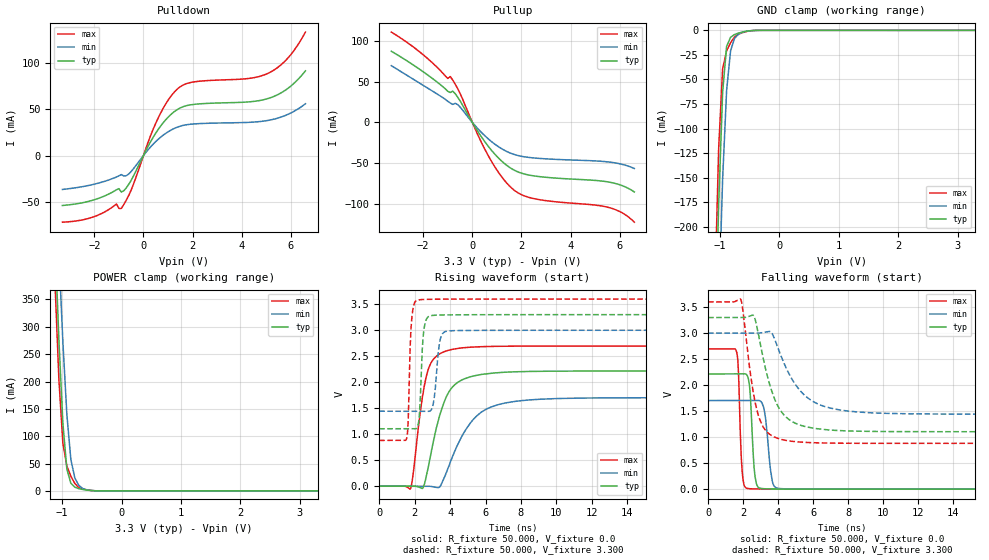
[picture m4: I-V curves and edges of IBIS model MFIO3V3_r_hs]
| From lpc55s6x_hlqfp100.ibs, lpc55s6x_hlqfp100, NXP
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|   Model MFIO3V3_r_hs
[Model] MFIO3V3_r_hs
Model_type I/O
Polarity   Non-Inverting
Enable   Active-Low
Vinl =  0.990V
Vinh =  2.310V
Vmeas =  1.650V
Cref =  0.0F
Rref =  100.000
Vref =  0.0V
C_comp   1.925pF   1.906pF   1.947pF
C_comp_pullup   1.145pF   1.141pF   1.152pF
C_comp_pulldown   0.641pF   0.633pF   0.647pF
[Model Spec]
Vinh   2.310V   2.100V   2.520V
Vinl   0.990V   0.900V   1.080V
Vmeas   1.650V   1.500V   1.800V
Vref   0.0V   0.0V   0.0V
Cref   0.0F   0.0F   0.0F
Rref   100.000   100.000   100.000
[Temperature Range]   25.000   0.125k   -40.000
[Voltage Range]   3.300V   3.000V   3.600V
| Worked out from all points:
|   slope of the pulldown table from 0 to 0.495 V, typ, clamps not added: 20.7 ohm
|   slope of the pullup table from 0 to 0.495 V, typ, clamps not added: 21.4 ohm
|   GND clamp passes 1 mA (typ) near -0.56 V on its own axis
|   POWER clamp passes 1 mA (typ) near -0.54 V on its own axis
|   rising waveform, R_fixture 50.000, V_fixture 0.0: 20-80 % time 1.05ns typ, 1.66ns min, 671ps max; typ from 0 V to 2.21 V
|   rising waveform, R_fixture 50.000, V_fixture 3.300: 20-80 % time 177ps typ, 249ps min, 147ps max; typ from 1.1 V to 3.3 V
|   falling waveform, R_fixture 50.000, V_fixture 0.0: 20-80 % time 203ps typ, 295ps min, 162ps max; typ from 2.21 V to 0 V
|   falling waveform, R_fixture 50.000, V_fixture 3.300: 20-80 % time 1.14ns typ, 1.67ns min, 742ps max; typ from 3.3 V to 1.1 V
[Pulldown]
|Voltage   I(typ)   I(min)   I(max)
-3.3V     -53.7mA    -36.43mA   -71.67mA
-2.1V     -48.29mA   -31.37mA   -66.51mA
-1.1V     -36.82mA   -23.05mA   -52.1mA
-900mV    -39.2mA    -20.39mA   -56.91mA
-600mV    -30.96mA   -19.83mA   -42.97mA
600mV     28.07mA    17.5mA     40.4mA
1V        41.17mA    25.53mA    59.41mA
1.4V      49.87mA    30.79mA    72.04mA
2V        54.93mA    33.94mA    79.03mA
5V        60.84mA    37.53mA    87.68mA
5.9V      72.62mA    44.52mA    105.4mA
6.6V      91.19mA    55.78mA    132.9mA
[Pullup]
|Voltage   I(typ)   I(min)   I(max)
-3.3V     87.16mA    69.54mA    110.7mA
-2.1V     64.12mA    47.22mA    85.31mA
-1V       38.1mA     25.85mA    53.88mA
-900mV    36.64mA    23.75mA    56.16mA
-800mV    38.25mA    22.02mA    51.93mA
-600mV    31.06mA    21.93mA    41.58mA
700mV     -31.25mA   -21.55mA   -43.56mA
1.2V      -47.6mA    -32.42mA   -66.97mA
1.7V      -58.52mA   -39.3mA    -83.05mA
2.6V      -66.01mA   -43.88mA   -94.06mA
5.6V      -73.4mA    -48.74mA   -104.7mA
6.6V      -85.32mA   -56.6mA    -122.4mA
[GND_clamp]
|Voltage   I(typ)   I(min)   I(max)
-3.3V     -7.222A    -7.177A    -7.278A
-1.089V   -337.1mA   -440.8mA   -274.1mA
-1.022V   -178.2mA   -284.2mA   -121mA
-955mV    -63.05mA   -151.6mA   -39.25mA
-888mV    -16.33mA   -61.34mA   -20.9mA
-821mV    -7.066mA   -20.84mA   -12.66mA
-754mV    -4.265mA   -8.157mA   -6.693mA
-687mV    -2.794mA   -3.896mA   -3.841mA
-620mV    -1.725mA   -1.894mA   -2.339mA
-419mV    -112.4uA   -138.2uA   -135uA
3.3V      0A         0A         -7.009uA
[POWER_clamp]
|Voltage   I(typ)   I(min)   I(max)
-3.3V     8.016A     7.986A     8.074A
-1.122V   463.7mA    614.3mA    385mA
-1.055V   276.3mA    434.9mA    203.9mA
-988mV    124mA      272.3mA    87.13mA
-921mV    39.96mA    140.1mA    45.6mA
-854mV    14.17mA    57.77mA    27.03mA
-787mV    6.855mA    23.75mA    13.68mA
-720mV    4.075mA    10.22mA    6.123mA
-653mV    2.616mA    4.368mA    3.615mA
-586mV    1.55mA     1.867mA    2.107mA
-452mV    281.1uA    359.9uA    338.7uA
3.3V      0A         0A         7.017uA
[Ramp]
| variable   typ   min   max
dV/dt_r   1.329/1.050n   1.022/1.662n   1.618/0.671n
dV/dt_f   1.317/1.135n   0.935/1.672n   1.632/0.745n
R_load = 50.000
[Rising Waveform]
R_fixture= 50.000
V_fixture= 0.0
V_fixture_min= 0.0
V_fixture_max= 0.0
|time   V(typ)   V(min)   V(max)
0s        11.38nV    124.8nV    46.5nV
1.76ns    11.35uV    -454.5nV   -52.4mV
1.89ns    125.5uV    -342.1nV   156mV
2.47ns    -34.61mV   71.44uV    1.767V
2.93ns    645.9mV    -5.154mV   2.378V
3.68ns    1.636V     173.9mV    2.589V
4.98ns    2.088V     1.138V     2.67V
6.67ns    2.183V     1.564V     2.691V
11.05ns   2.214V     1.693V     2.696V
100ns     2.215V     1.704V     2.696V
[Rising Waveform]
R_fixture= 50.000
V_fixture= 3.300
V_fixture_min= 3.000
V_fixture_max= 3.600
|time   V(typ)   V(min)   V(max)
0s        1.105V     1.442V     880.4mV
1.55ns    1.105V     1.442V     919.2mV
1.84ns    1.105V     1.442V     3.234V
2.22ns    1.223V     1.442V     3.583V
2.38ns    2.203V     1.442V     3.59V
2.7ns     3.235V     1.441V     3.594V
3.07ns    3.287V     1.618V     3.596V
3.47ns    3.293V     2.857V     3.598V
4.1ns     3.296V     2.991V     3.599V
100ns     3.3V       3V         3.6V
[Falling Waveform]
R_fixture= 50.000
V_fixture= 0.0
V_fixture_min= 0.0
V_fixture_max= 0.0
|time   V(typ)   V(min)   V(max)
0s        2.215V     1.704V     2.696V
1.63ns    2.215V     1.704V     2.641V
1.73ns    2.215V     1.704V     2.3V
1.97ns    2.216V     1.704V     265.9mV
2.38ns    1.949V     1.704V     8.551mV
2.68ns    252.6mV    1.704V     4.207mV
3.21ns    8.403mV    1.523V     1.553mV
3.68ns    3.793mV    139.7mV    954.6uV
4.26ns    2.189mV    8.488mV    558.3uV
100ns     15.88nV    132.9nV    49.27nV
[Falling Waveform]
R_fixture= 50.000
V_fixture= 3.300
V_fixture_min= 3.000
V_fixture_max= 3.600
|time   V(typ)   V(min)   V(max)
0s        3.3V       3V         3.6V
1.87ns    3.3V       3V         3.648V
2.61ns    3.334V     3V         1.81V
3.09ns    2.622V     3.009V     1.234V
3.56ns    1.971V     3.029V     1.046V
3.83ns    1.711V     2.868V     996.5mV
5.1ns     1.252V     1.964V     910mV
6.88ns    1.14V      1.569V     886.3mV
10.87ns   1.107V     1.453V     880.6mV
100ns     1.105V     1.442V     880.4mV
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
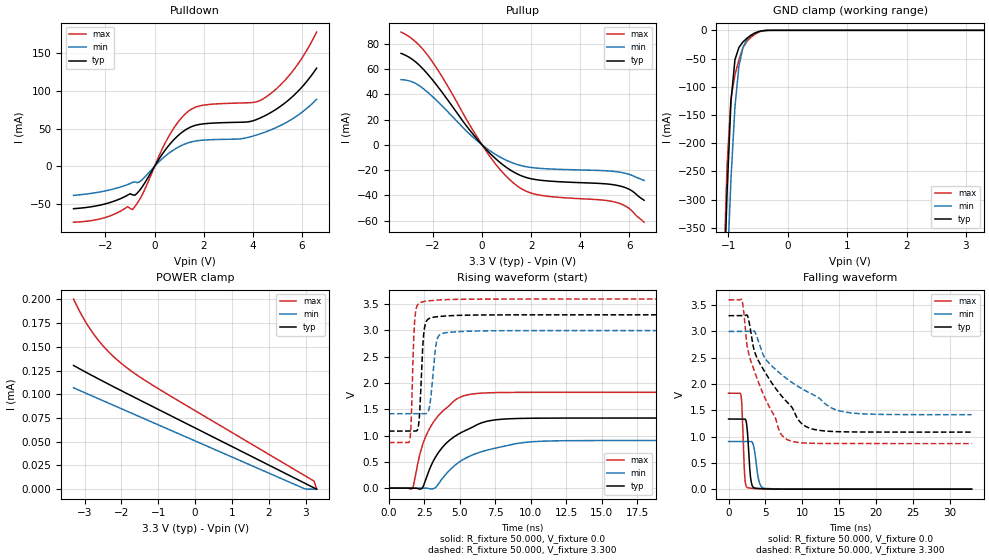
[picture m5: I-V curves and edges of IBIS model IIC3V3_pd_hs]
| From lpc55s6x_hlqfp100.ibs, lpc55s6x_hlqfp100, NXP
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|   Model IIC3V3_pd_hs
[Model] IIC3V3_pd_hs
Model_type I/O
Polarity   Non-Inverting
Enable   Active-Low
Vinl =  0.990V
Vinh =  2.310V
Vmeas =  1.650V
Cref =  0.0F
Rref =  100.000
Vref =  0.0V
C_comp   2.434pF   2.433pF   2.440pF
C_comp_pullup   0.538pF   0.435pF   0.627pF
C_comp_pulldown   1.615pF   1.554pF   1.667pF
[Model Spec]
Vinh   2.310V   2.100V   2.520V
Vinl   0.990V   0.900V   1.080V
Vmeas   1.650V   1.500V   1.800V
Vref   0.0V   0.0V   0.0V
Cref   0.0F   0.0F   0.0F
Rref   100.000   100.000   100.000
[Temperature Range]   25.000   0.125k   -40.000
[Voltage Range]   3.300V   3.000V   3.600V
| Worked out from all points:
|   slope of the pulldown table from 0 to 0.495 V, typ, clamps not added: 20.4 ohm
|   slope of the pullup table from 0 to 0.495 V, typ, clamps not added: 49.8 ohm
|   GND clamp passes 1 mA (typ) near -0.43 V on its own axis
|   rising waveform, R_fixture 50.000, V_fixture 0.0: 20-80 % time 2.43ns typ, 3.18ns min, 1.81ns max; typ from 0 V to 1.33 V
|   rising waveform, R_fixture 50.000, V_fixture 3.300: 20-80 % time 241ps typ, 336ps min, 194ps max; typ from 1.08 V to 3.3 V
|   falling waveform, R_fixture 50.000, V_fixture 0.0: 20-80 % time 379ps typ, 544ps min, 287ps max; typ from 1.33 V to 0 V
|   falling waveform, R_fixture 50.000, V_fixture 3.300: 20-80 % time 5.55ns typ, 7.91ns min, 3.87ns max; typ from 3.3 V to 1.08 V
[Pulldown]
|Voltage   I(typ)   I(min)   I(max)
-3.3V     -56mA      -38.4mA    -73.87mA
-2.1V     -50.37mA   -33.07mA   -68.52mA
-1.1V     -38.15mA   -24.11mA   -53.37mA
-900mV    -37.61mA   -21.16mA   -57.18mA
-500mV    -26.92mA   -17.4mA    -37.43mA
500mV     24.51mA    15.34mA    35.14mA
1.2V      47.07mA    29.16mA    67.89mA
1.9V      55.94mA    34.55mA    80.54mA
3.8V      58.93mA    38.31mA    84.23mA
4.5V      67.15mA    45.39mA    91.04mA
5.6V      91.85mA    62.59mA    125mA
6.6V      130mA      88.72mA    177.8mA
[Pullup]
|Voltage   I(typ)   I(min)   I(max)
-3.3V     72.4mA     51.62mA    89.28mA
-2.8V     67.12mA    49.5mA     83.13mA
-2.2V     55.65mA    41.38mA    70.52mA
-1.6V     40.88mA    30.27mA    53.04mA
-600mV    14.09mA    10.23mA    18.91mA
200mV     -4.263mA   -2.967mA   -5.9mA
800mV     -15.05mA   -10.35mA   -21.01mA
1.4V      -22.69mA   -15.36mA   -32.04mA
2.4V      -28.05mA   -18.66mA   -39.95mA
5.5V      -32.06mA   -21.31mA   -45.72mA
6V        -35.26mA   -23.41mA   -50.46mA
6.6V      -43.87mA   -28.15mA   -61.22mA
[GND_clamp]
|Voltage   I(typ)   I(min)   I(max)
-3.3V     -10.05A    -9.18A     -11.33A
-1.089V   -516.5mA   -633.7mA   -475mA
-1.022V   -291.9mA   -436.3mA   -243.2mA
-955mV    -126mA     -264mA     -120.7mA
-888mV    -52.17mA   -135.6mA   -79.12mA
-821mV    -30.44mA   -63.69mA   -52.12mA
-754mV    -20.67mA   -30.69mA   -31.05mA
-687mV    -14.19mA   -15.97mA   -19.65mA
-553mV    -5.021mA   -4.512mA   -7.044mA
-419mV    -659.6uA   -714.3uA   -896.4uA
-285mV    -20.38uA   -37.42uA   -22.84uA
3.3V      0A         0A         0A
[POWER_clamp]
|Voltage   I(typ)   I(min)   I(max)
-3.3V     130.3uA    106.8uA    200.3uA
-3.132V   126.7uA    103.9uA    187.1uA
-2.998V   123.9uA    101.7uA    177.8uA
-2.73V    118.4uA    97.1uA     162.1uA
-2.529V   114.3uA    93.69uA    152.3uA
-2.328V   110.2uA    90.28uA    143.9uA
-1.926V   102.2uA    83.47uA    130.1uA
-1.524V   94.32uA    76.66uA    118.8uA
-921mV    82.52uA    66.44uA    104uA
2.965V    6.549uA    592.5nA    14.59uA
3.233V    1.309uA    0A         8.433uA
3.3V      0A         0A         0A
[Ramp]
| variable   typ   min   max
dV/dt_r   0.800/2.433n   0.544/3.184n   1.094/1.812n
dV/dt_f   1.328/5.547n   0.950/7.909n   1.639/3.869n
R_load = 50.000
[Rising Waveform]
R_fixture= 50.000
V_fixture= 0.0
V_fixture_min= 0.0
V_fixture_max= 0.0
|time   V(typ)   V(min)   V(max)
0s        10.23nV    71.93nV    30.73nV
1.632ns   18.86uV    71.42nV    -10.83mV
2.343ns   370.2uV    76.31uV    798.8mV
2.982ns   433.5mV    -16.05mV   1.188V
3.344ns   617mV      25.85mV    1.333V
4.042ns   853.9mV    273.8mV    1.521V
5.586ns   1.119V     594.1mV    1.777V
7.276ns   1.29V      747mV      1.816V
10.76ns   1.331V     891.7mV    1.823V
33ns      1.333V     906mV      1.823V
[Rising Waveform]
R_fixture= 50.000
V_fixture= 3.300
V_fixture_min= 3.000
V_fixture_max= 3.600
|time   V(typ)   V(min)   V(max)
0s        1.085V     1.415V     866.6mV
1.466ns   1.085V     1.415V     907.3mV
1.828ns   1.084V     1.415V     3.224V
2.114ns   1.254V     1.415V     3.516V
2.319ns   2.35V      1.415V     3.542V
2.621ns   3.166V     1.416V     3.558V
2.907ns   3.237V     1.621V     3.567V
3.355ns   3.261V     2.784V     3.579V
3.89ns    3.275V     2.952V     3.587V
33ns      3.298V     2.999V     3.598V
[Falling Waveform]
R_fixture= 50.000
V_fixture= 0.0
V_fixture_min= 0.0
V_fixture_max= 0.0
|time   V(typ)   V(min)   V(max)
0s        1.333V     906.1mV    1.824V
1.671ns   1.333V     906.1mV    1.8V
1.839ns   1.333V     906.1mV    1.516V
2.194ns   1.335V     906.1mV    248.2mV
2.592ns   1.034V     906.1mV    28.56mV
3.005ns   201.2mV    907.4mV    17.6mV
3.548ns   22.18mV    715.7mV    12.27mV
4.118ns   13.25mV    159.7mV    5.625mV
4.898ns   6.293mV    16.27mV    2.275mV
33ns      662nV      1.301uV    429.9nV
[Falling Waveform]
R_fixture= 50.000
V_fixture= 3.300
V_fixture_min= 3.000
V_fixture_max= 3.600
|time   V(typ)   V(min)   V(max)
0s        3.298V     2.999V     3.598V
1.815ns   3.298V     2.999V     3.606V
2.477ns   3.311V     2.999V     2.767V
2.917ns   3.081V     2.998V     2.483V
3.918ns   2.48V      2.868V     2.086V
5.055ns   2.199V     2.47V      1.699V
7.793ns   1.678V     2.112V     955.7mV
12.03ns   1.124V     1.756V     869.9mV
16.66ns   1.088V     1.45V      866.9mV
33ns      1.085V     1.416V     866.6mV
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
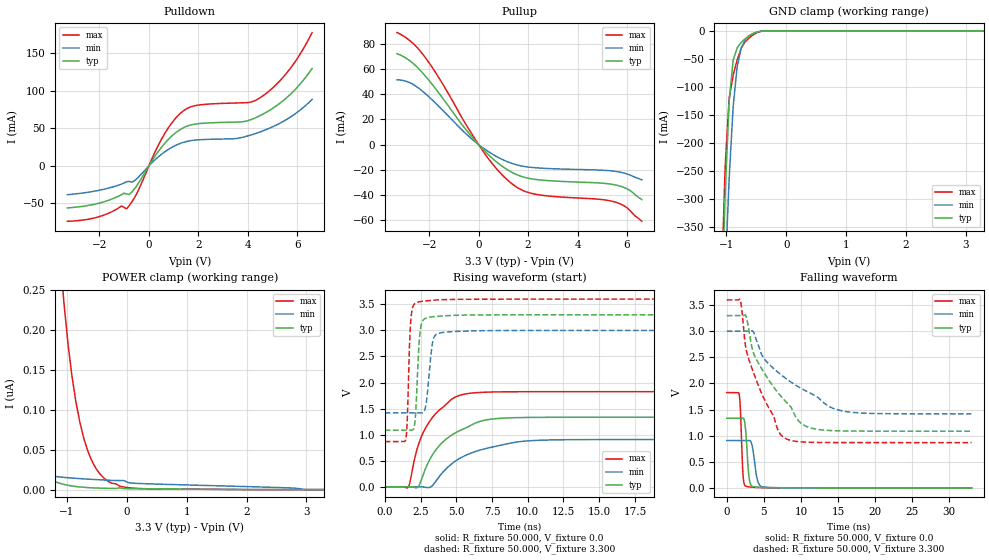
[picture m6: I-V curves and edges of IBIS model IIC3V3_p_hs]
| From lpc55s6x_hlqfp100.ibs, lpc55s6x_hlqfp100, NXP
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|   Model IIC3V3_p_hs
[Model] IIC3V3_p_hs
Model_type I/O
Polarity   Non-Inverting
Enable   Active-Low
Vinl =  0.990V
Vinh =  2.310V
Vmeas =  1.650V
Cref =  0.0F
Rref =  100.000
Vref =  0.0V
C_comp   2.434pF   2.433pF   2.440pF
C_comp_pullup   0.538pF   0.436pF   0.627pF
C_comp_pulldown   1.614pF   1.554pF   1.665pF
[Model Spec]
Vinh   2.310V   2.100V   2.520V
Vinl   0.990V   0.900V   1.080V
Vmeas   1.650V   1.500V   1.800V
Vref   0.0V   0.0V   0.0V
Cref   0.0F   0.0F   0.0F
Rref   100.000   100.000   100.000
[Temperature Range]   25.000   0.125k   -40.000
[Voltage Range]   3.300V   3.000V   3.600V
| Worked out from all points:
|   slope of the pulldown table from 0 to 0.495 V, typ, clamps not added: 20.4 ohm
|   slope of the pullup table from 0 to 0.495 V, typ, clamps not added: 49.8 ohm
|   GND clamp passes 1 mA (typ) near -0.43 V on its own axis
|   rising waveform, R_fixture 50.000, V_fixture 0.0: 20-80 % time 2.44ns typ, 3.19ns min, 1.82ns max; typ from 0 V to 1.33 V
|   rising waveform, R_fixture 50.000, V_fixture 3.300: 20-80 % time 241ps typ, 336ps min, 194ps max; typ from 1.08 V to 3.3 V
|   falling waveform, R_fixture 50.000, V_fixture 0.0: 20-80 % time 379ps typ, 544ps min, 287ps max; typ from 1.33 V to 0 V
|   falling waveform, R_fixture 50.000, V_fixture 3.300: 20-80 % time 5.55ns typ, 7.92ns min, 3.87ns max; typ from 3.3 V to 1.08 V
[Pulldown]
|Voltage   I(typ)   I(min)   I(max)
-3.3V     -56mA      -38.4mA    -73.87mA
-2.1V     -50.37mA   -33.07mA   -68.52mA
-1.1V     -38.15mA   -24.11mA   -53.37mA
-900mV    -37.61mA   -21.16mA   -57.18mA
-500mV    -26.92mA   -17.4mA    -37.43mA
500mV     24.51mA    15.34mA    35.14mA
1.2V      47.07mA    29.16mA    67.89mA
1.9V      55.94mA    34.55mA    80.54mA
3.8V      58.93mA    38.31mA    84.23mA
4.5V      67.16mA    45.4mA     91.05mA
5.6V      91.88mA    62.62mA    125.1mA
6.6V      130mA      88.76mA    177.9mA
[Pullup]
|Voltage   I(typ)   I(min)   I(max)
-3.3V     72.44mA    51.65mA    89.33mA
-2.8V     67.15mA    49.53mA    83.18mA
-2.2V     55.68mA    41.4mA     70.55mA
-1.6V     40.9mA     30.28mA    53.06mA
-600mV    14.09mA    10.23mA    18.92mA
200mV     -4.263mA   -2.967mA   -5.9mA
800mV     -15.05mA   -10.35mA   -21.01mA
1.4V      -22.69mA   -15.36mA   -32.04mA
2.4V      -28.05mA   -18.66mA   -39.95mA
5.5V      -32.06mA   -21.31mA   -45.72mA
6V        -35.26mA   -23.41mA   -50.46mA
6.6V      -43.87mA   -28.15mA   -61.22mA
[GND_clamp]
|Voltage   I(typ)   I(min)   I(max)
-3.3V     -10.05A    -9.18A     -11.33A
-1.089V   -516.5mA   -633.7mA   -475mA
-1.022V   -291.8mA   -436.3mA   -243.2mA
-955mV    -126mA     -264mA     -120.7mA
-888mV    -52.17mA   -135.6mA   -79.11mA
-821mV    -30.43mA   -63.68mA   -52.11mA
-754mV    -20.66mA   -30.68mA   -31.04mA
-687mV    -14.18mA   -15.96mA   -19.64mA
-553mV    -5.013mA   -4.505mA   -7.034mA
-419mV    -652.2uA   -708.2uA   -887.6uA
-285mV    -14.83uA   -32.68uA   -16.3uA
3.3V      0A         0A         0A
[POWER_clamp]
|Voltage   I(typ)   I(min)   I(max)
-3.3V     1.337uA    96.84nA    41.74uA
-2.395V   241.1nA    38.51nA    8.841uA
-2.194V   152.2nA    32.17nA    5.805uA
-1.926V   78.16nA    25.86nA    3.134uA
-1.658V   37.82nA    21.36nA    1.572uA
-1.256V   11.75nA    16.9nA     472.7nA
-1.055V   6.592nA    15.36nA    237.1nA
-921mV    4.605nA    14.51nA    144.1nA
-787mV    3.339nA    13.77nA    84.89nA
-586mV    2.257nA    12.84nA    36.19nA
-318mV    1.588nA    11.83nA    10.67nA
3.3V      0A         0A         0A
[Ramp]
| variable   typ   min   max
dV/dt_r   0.801/2.438n   0.544/3.191n   1.095/1.816n
dV/dt_f   1.329/5.554n   0.950/7.920n   1.640/3.875n
R_load = 50.000
[Rising Waveform]
R_fixture= 50.000
V_fixture= 0.0
V_fixture_min= 0.0
V_fixture_max= 0.0
|time   V(typ)   V(min)   V(max)
0s        11.16nV    74.81nV    32.72nV
1.636ns   21.13uV    74.28nV    -9.633mV
2.345ns   1.006mV    77.15uV    800.3mV
2.981ns   432.7mV    -16.03mV   1.188V
3.312ns   602.9mV    17.15mV    1.322V
4.008ns   844.8mV    263.4mV    1.514V
5.569ns   1.117V     591.9mV    1.777V
7.277ns   1.291V     747.1mV    1.817V
10.77ns   1.332V     892.2mV    1.824V
33ns      1.334V     906.7mV    1.825V
[Rising Waveform]
R_fixture= 50.000
V_fixture= 3.300
V_fixture_min= 3.000
V_fixture_max= 3.600
|time   V(typ)   V(min)   V(max)
0s        1.085V     1.416V     866.9mV
1.461ns   1.085V     1.416V     902.1mV
1.562ns   1.085V     1.416V     1.207V
1.829ns   1.085V     1.416V     3.227V
2.113ns   1.252V     1.416V     3.516V
2.321ns   2.359V     1.416V     3.543V
2.62ns    3.166V     1.417V     3.559V
3.356ns   3.262V     2.787V     3.58V
3.889ns   3.275V     2.953V     3.588V
33ns      3.3V       3V         3.6V
[Falling Waveform]
R_fixture= 50.000
V_fixture= 0.0
V_fixture_min= 0.0
V_fixture_max= 0.0
|time   V(typ)   V(min)   V(max)
0s        1.335V     906.8mV    1.825V
1.67ns    1.335V     906.8mV    1.802V
1.838ns   1.335V     906.8mV    1.52V
2.198ns   1.336V     906.8mV    242mV
2.58ns    1.056V     906.8mV    29.94mV
2.991ns   217.6mV    908mV      18.39mV
3.533ns   23.19mV    729.3mV    12.88mV
4.116ns   13.68mV    161.5mV    5.928mV
4.876ns   6.734mV    17.08mV    2.537mV
33ns      1.201uV    3.06uV     529.5nV
[Falling Waveform]
R_fixture= 50.000
V_fixture= 3.300
V_fixture_min= 3.000
V_fixture_max= 3.600
|time   V(typ)   V(min)   V(max)
0s        3.3V       3V         3.6V
1.816ns   3.3V       3V         3.608V
2.492ns   3.313V     3V         2.756V
2.918ns   3.081V     3V         2.486V
3.943ns   2.475V     2.86V      2.079V
5.059ns   2.2V       2.472V     1.701V
7.802ns   1.679V     2.113V     956mV
12.04ns   1.125V     1.757V     870.3mV
16.68ns   1.088V     1.451V     867.2mV
33ns      1.085V     1.416V     866.9mV
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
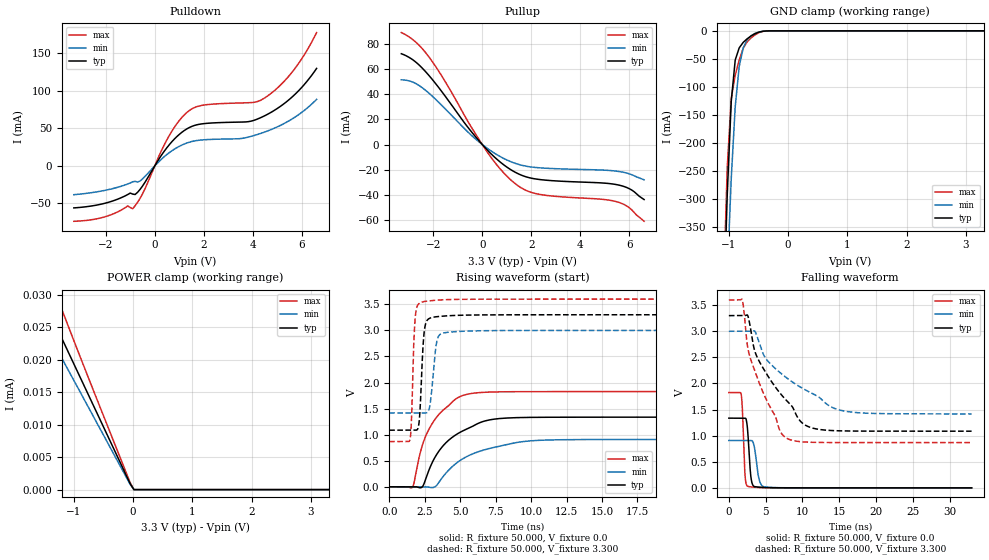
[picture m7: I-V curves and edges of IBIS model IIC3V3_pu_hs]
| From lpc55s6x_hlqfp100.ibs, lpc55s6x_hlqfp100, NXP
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|   Model IIC3V3_pu_hs
[Model] IIC3V3_pu_hs
Model_type I/O
Polarity   Non-Inverting
Enable   Active-Low
Vinl =  0.990V
Vinh =  2.310V
Vmeas =  1.650V
Cref =  0.0F
Rref =  100.000
Vref =  0.0V
C_comp   2.434pF   2.433pF   2.440pF
C_comp_pullup   0.539pF   0.438pF   0.626pF
C_comp_pulldown   1.614pF   1.554pF   1.665pF
[Model Spec]
Vinh   2.310V   2.100V   2.520V
Vinl   0.990V   0.900V   1.080V
Vmeas   1.650V   1.500V   1.800V
Vref   0.0V   0.0V   0.0V
Cref   0.0F   0.0F   0.0F
Rref   100.000   100.000   100.000
[Temperature Range]   25.000   0.125k   -40.000
[Voltage Range]   3.300V   3.000V   3.600V
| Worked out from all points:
|   slope of the pulldown table from 0 to 0.495 V, typ, clamps not added: 20.4 ohm
|   slope of the pullup table from 0 to 0.495 V, typ, clamps not added: 49.8 ohm
|   GND clamp passes 1 mA (typ) near -0.43 V on its own axis
|   rising waveform, R_fixture 50.000, V_fixture 0.0: 20-80 % time 2.43ns typ, 3.18ns min, 1.81ns max; typ from 0.001 V to 1.34 V
|   rising waveform, R_fixture 50.000, V_fixture 3.300: 20-80 % time 241ps typ, 335ps min, 194ps max; typ from 1.09 V to 3.3 V
|   falling waveform, R_fixture 50.000, V_fixture 0.0: 20-80 % time 379ps typ, 544ps min, 287ps max; typ from 1.34 V to 0.001 V
|   falling waveform, R_fixture 50.000, V_fixture 3.300: 20-80 % time 5.55ns typ, 7.92ns min, 3.88ns max; typ from 3.3 V to 1.09 V
[Pulldown]
|Voltage   I(typ)   I(min)   I(max)
-3.3V     -56mA      -38.4mA    -73.87mA
-2.1V     -50.37mA   -33.07mA   -68.52mA
-1.1V     -38.15mA   -24.11mA   -53.37mA
-900mV    -37.61mA   -21.16mA   -57.18mA
-500mV    -26.92mA   -17.4mA    -37.43mA
500mV     24.51mA    15.34mA    35.14mA
1.2V      47.07mA    29.16mA    67.89mA
1.9V      55.94mA    34.55mA    80.54mA
3.8V      58.93mA    38.31mA    84.23mA
4.5V      67.15mA    45.39mA    91.04mA
5.6V      91.85mA    62.59mA    125mA
6.6V      130mA      88.72mA    177.8mA
[Pullup]
|Voltage   I(typ)   I(min)   I(max)
-3.3V     72.4mA     51.62mA    89.28mA
-2.8V     67.12mA    49.5mA     83.13mA
-2.2V     55.65mA    41.38mA    70.52mA
-1.6V     40.88mA    30.27mA    53.04mA
-600mV    14.09mA    10.23mA    18.91mA
200mV     -4.263mA   -2.967mA   -5.9mA
800mV     -15.05mA   -10.35mA   -21.01mA
1.4V      -22.69mA   -15.36mA   -32.04mA
2.4V      -28.05mA   -18.66mA   -39.95mA
5.5V      -32.06mA   -21.31mA   -45.72mA
6V        -35.26mA   -23.41mA   -50.46mA
6.6V      -43.88mA   -28.16mA   -61.22mA
[GND_clamp]
|Voltage   I(typ)   I(min)   I(max)
-3.3V     -10.05A    -9.18A     -11.33A
-1.089V   -516.6mA   -633.8mA   -475.1mA
-1.022V   -291.9mA   -436.4mA   -243.3mA
-955mV    -126.1mA   -264.1mA   -120.8mA
-888mV    -52.24mA   -135.7mA   -79.2mA
-821mV    -30.5mA    -63.74mA   -52.2mA
-754mV    -20.73mA   -30.74mA   -31.13mA
-687mV    -14.25mA   -16.02mA   -19.73mA
-553mV    -5.085mA   -4.563mA   -7.127mA
-419mV    -724uA     -765.2uA   -978.9uA
-285mV    -84.74uA   -88.26uA   -105.4uA
3.3V      0A         0A         0A
[POWER_clamp]
|Voltage   I(typ)   I(min)   I(max)
-3.3V     65.36uA    55.62uA    117.1uA
-1.792V   34.89uA    30.26uA    43.22uA
-1.725V   33.58uA    29.13uA    41.33uA
-1.524V   29.67uA    25.75uA    35.94uA
-1.323V   25.75uA    22.36uA    30.85uA
-1.256V   24.45uA    21.23uA    29.21uA
-921mV    17.94uA    15.59uA    21.23uA
-318mV    6.202uA    5.398uA    7.298uA
-50mV     976.9nA    858.9nA    1.15uA
17mV      0A         0A         0A
3.3V      0A         0A         0A
[Ramp]
| variable   typ   min   max
dV/dt_r   0.801/2.431n   0.544/3.183n   1.095/1.810n
dV/dt_f   1.328/5.554n   0.950/7.918n   1.639/3.876n
R_load = 50.000
[Rising Waveform]
R_fixture= 50.000
V_fixture= 0.0
V_fixture_min= 0.0
V_fixture_max= 0.0
|time   V(typ)   V(min)   V(max)
0s        843.5uV    916.9uV    820.9uV
1.635ns   864.2uV    916.9uV    -8.633mV
2.34ns    995.9uV    991.8uV    799.9mV
2.979ns   434.6mV    -14.96mV   1.191V
3.321ns   609.9mV    21.19mV    1.329V
4.014ns   849.3mV    267.8mV    1.519V
5.57ns    1.12V      594.4mV    1.78V
7.282ns   1.293V     749.7mV    1.819V
10.75ns   1.334V     894mV      1.826V
33ns      1.336V     908.3mV    1.826V
[Rising Waveform]
R_fixture= 50.000
V_fixture= 3.300
V_fixture_min= 3.000
V_fixture_max= 3.600
|time   V(typ)   V(min)   V(max)
0s        1.086V     1.417V     867.9mV
1.466ns   1.086V     1.417V     908.6mV
1.828ns   1.086V     1.417V     3.227V
2.113ns   1.253V     1.417V     3.518V
2.32ns    2.357V     1.417V     3.545V
2.619ns   3.167V     1.418V     3.56V
2.898ns   3.238V     1.606V     3.569V
3.375ns   3.264V     2.811V     3.581V
3.892ns   3.276V     2.954V     3.589V
33ns      3.3V       3V         3.6V
[Falling Waveform]
R_fixture= 50.000
V_fixture= 0.0
V_fixture_min= 0.0
V_fixture_max= 0.0
|time   V(typ)   V(min)   V(max)
0s        1.336V     908.4mV    1.826V
1.67ns    1.336V     908.4mV    1.804V
1.852ns   1.336V     908.4mV    1.481V
2.197ns   1.337V     908.4mV    245.1mV
2.583ns   1.053V     908.4mV    30.63mV
3.01ns    197.9mV    909.7mV    18.93mV
3.527ns   24.35mV    736.1mV    13.73mV
4.131ns   14.47mV    154.9mV    6.499mV
4.881ns   7.459mV    17.98mV    3.191mV
33ns      844.2uV    918.2uV    821.3uV
[Falling Waveform]
R_fixture= 50.000
V_fixture= 3.300
V_fixture_min= 3.000
V_fixture_max= 3.600
|time   V(typ)   V(min)   V(max)
0s        3.3V       3V         3.6V
1.819ns   3.3V       3V         3.607V
2.485ns   3.313V     3V         2.763V
2.922ns   3.078V     3V         2.484V
3.968ns   2.468V     2.85V      2.07V
5.057ns   2.201V     2.472V     1.702V
7.813ns   1.678V     2.112V     955.8mV
12.04ns   1.125V     1.757V     871.1mV
16.67ns   1.089V     1.451V     868.1mV
33ns      1.086V     1.417V     867.9mV
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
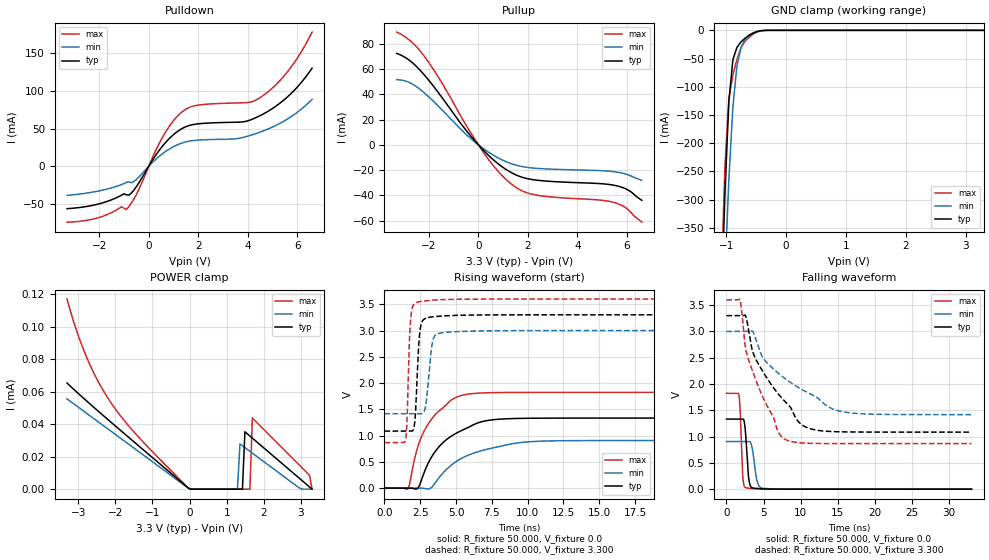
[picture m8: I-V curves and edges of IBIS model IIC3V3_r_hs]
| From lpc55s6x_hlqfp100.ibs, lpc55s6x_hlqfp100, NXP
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|   Model IIC3V3_r_hs
[Model] IIC3V3_r_hs
Model_type I/O
Polarity   Non-Inverting
Enable   Active-Low
Vinl =  0.990V
Vinh =  2.310V
Vmeas =  1.650V
Cref =  0.0F
Rref =  100.000
Vref =  0.0V
C_comp   2.434pF   2.433pF   2.440pF
C_comp_pullup   0.538pF   0.435pF   0.627pF
C_comp_pulldown   1.615pF   1.554pF   1.667pF
[Model Spec]
Vinh   2.310V   2.100V   2.520V
Vinl   0.990V   0.900V   1.080V
Vmeas   1.650V   1.500V   1.800V
Vref   0.0V   0.0V   0.0V
Cref   0.0F   0.0F   0.0F
Rref   100.000   100.000   100.000
[Temperature Range]   25.000   0.125k   -40.000
[Voltage Range]   3.300V   3.000V   3.600V
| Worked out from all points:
|   slope of the pulldown table from 0 to 0.495 V, typ, clamps not added: 20.4 ohm
|   slope of the pullup table from 0 to 0.495 V, typ, clamps not added: 49.8 ohm
|   GND clamp passes 1 mA (typ) near -0.43 V on its own axis
|   rising waveform, R_fixture 50.000, V_fixture 0.0: 20-80 % time 2.43ns typ, 3.18ns min, 1.81ns max; typ from 0 V to 1.33 V
|   rising waveform, R_fixture 50.000, V_fixture 3.300: 20-80 % time 241ps typ, 336ps min, 194ps max; typ from 1.08 V to 3.3 V
|   falling waveform, R_fixture 50.000, V_fixture 0.0: 20-80 % time 379ps typ, 543ps min, 287ps max; typ from 1.33 V to 0 V
|   falling waveform, R_fixture 50.000, V_fixture 3.300: 20-80 % time 5.56ns typ, 7.92ns min, 3.88ns max; typ from 3.3 V to 1.08 V
[Pulldown]
|Voltage   I(typ)   I(min)   I(max)
-3.3V     -56mA      -38.4mA    -73.87mA
-2.1V     -50.37mA   -33.07mA   -68.52mA
-1.1V     -38.15mA   -24.11mA   -53.37mA
-900mV    -37.61mA   -21.16mA   -57.18mA
-500mV    -26.92mA   -17.4mA    -37.43mA
500mV     24.51mA    15.34mA    35.14mA
1.2V      47.07mA    29.16mA    67.89mA
1.9V      55.94mA    34.55mA    80.54mA
3.8V      58.93mA    38.31mA    84.23mA
4.5V      67.15mA    45.39mA    91.04mA
5.6V      91.85mA    62.59mA    125mA
6.6V      130mA      88.72mA    177.8mA
[Pullup]
|Voltage   I(typ)   I(min)   I(max)
-3.3V     72.4mA     51.62mA    89.28mA
-2.8V     67.12mA    49.5mA     83.13mA
-2.2V     55.65mA    41.38mA    70.52mA
-1.6V     40.88mA    30.27mA    53.04mA
-600mV    14.09mA    10.23mA    18.91mA
200mV     -4.263mA   -2.967mA   -5.9mA
800mV     -15.05mA   -10.35mA   -21.01mA
1.4V      -22.69mA   -15.36mA   -32.04mA
2.4V      -28.05mA   -18.66mA   -39.95mA
5.5V      -32.06mA   -21.31mA   -45.72mA
6V        -35.26mA   -23.41mA   -50.46mA
6.6V      -43.87mA   -28.15mA   -61.22mA
[GND_clamp]
|Voltage   I(typ)   I(min)   I(max)
-3.3V     -10.05A    -9.18A     -11.33A
-1.089V   -516.5mA   -633.7mA   -475mA
-1.022V   -291.9mA   -436.3mA   -243.2mA
-955mV    -126mA     -264mA     -120.7mA
-888mV    -52.17mA   -135.6mA   -79.12mA
-821mV    -30.44mA   -63.69mA   -52.12mA
-754mV    -20.67mA   -30.69mA   -31.05mA
-687mV    -14.19mA   -15.97mA   -19.65mA
-553mV    -5.021mA   -4.512mA   -7.044mA
-419mV    -659.6uA   -714.3uA   -896.4uA
-285mV    -20.38uA   -37.42uA   -22.84uA
3.3V      0A         0A         0A
[POWER_clamp]
|Voltage   I(typ)   I(min)   I(max)
-3.3V     65.36uA    55.62uA    117.1uA
-2.797V   54.84uA    47.15uA    82.63uA
-2.194V   42.78uA    37.02uA    55.95uA
-50mV     976.9nA    858.9nA    1.15uA
1.29V     0A         0A         0A
1.357V    0A         27.85uA    0A
1.424V    0A         26.71uA    0A
1.491V    35.37uA    25.58uA    0A
1.625V    32.75uA    23.31uA    0A
1.692V    31.44uA    22.17uA    43.84uA
3.233V    1.309uA    0A         8.433uA
3.3V      0A         0A         0A
[Ramp]
| variable   typ   min   max
dV/dt_r   0.800/2.433n   0.544/3.184n   1.094/1.812n
dV/dt_f   1.329/5.558n   0.950/7.919n   1.640/3.880n
R_load = 50.000
[Rising Waveform]
R_fixture= 50.000
V_fixture= 0.0
V_fixture_min= 0.0
V_fixture_max= 0.0
|time   V(typ)   V(min)   V(max)
0s        10.23nV    71.93nV    30.73nV
1.632ns   18.41uV    71.42nV    -10.83mV
2.343ns   370.2uV    76.38uV    799mV
2.994ns   440.6mV    -16.22mV   1.194V
3.338ns   614.4mV    24.06mV    1.331V
4.041ns   853.7mV    273.6mV    1.521V
5.616ns   1.123V     598mV      1.779V
7.276ns   1.29V      747mV      1.816V
10.76ns   1.331V     891.7mV    1.823V
33ns      1.333V     906mV      1.823V
[Rising Waveform]
R_fixture= 50.000
V_fixture= 3.300
V_fixture_min= 3.000
V_fixture_max= 3.600
|time   V(typ)   V(min)   V(max)
0s        1.085V     1.415V     866.6mV
1.467ns   1.085V     1.415V     908.4mV
1.83ns    1.084V     1.415V     3.23V
2.116ns   1.259V     1.415V     3.516V
2.32ns    2.353V     1.415V     3.542V
2.623ns   3.167V     1.416V     3.558V
2.908ns   3.237V     1.623V     3.567V
3.363ns   3.262V     2.794V     3.58V
3.91ns    3.275V     2.953V     3.589V
33ns      3.3V       3V         3.6V
[Falling Waveform]
R_fixture= 50.000
V_fixture= 0.0
V_fixture_min= 0.0
V_fixture_max= 0.0
|time   V(typ)   V(min)   V(max)
0s        1.333V     906.1mV    1.824V
1.67ns    1.333V     906.1mV    1.801V
1.854ns   1.333V     906.1mV    1.471V
2.198ns   1.335V     906.1mV    240.7mV
2.588ns   1.041V     906.1mV    28.77mV
3.009ns   197mV      907.4mV    17.53mV
3.545ns   22.29mV    718.5mV    12.31mV
4.126ns   13.2mV     155.9mV    5.562mV
4.876ns   6.448mV    16.73mV    2.328mV
33ns      662nV      1.301uV    429.9nV
[Falling Waveform]
R_fixture= 50.000
V_fixture= 3.300
V_fixture_min= 3.000
V_fixture_max= 3.600
|time   V(typ)   V(min)   V(max)
0s        3.3V       3V         3.6V
1.819ns   3.3V       3V         3.607V
2.49ns    3.313V     3V         2.758V
2.928ns   3.074V     3V         2.481V
3.948ns   2.474V     2.858V     2.078V
5.06ns    2.201V     2.472V     1.701V
7.817ns   1.677V     2.112V     954.3mV
12.21ns   1.12V      1.742V     869.5mV
16.67ns   1.088V     1.451V     866.9mV
33ns      1.085V     1.417V     866.6mV
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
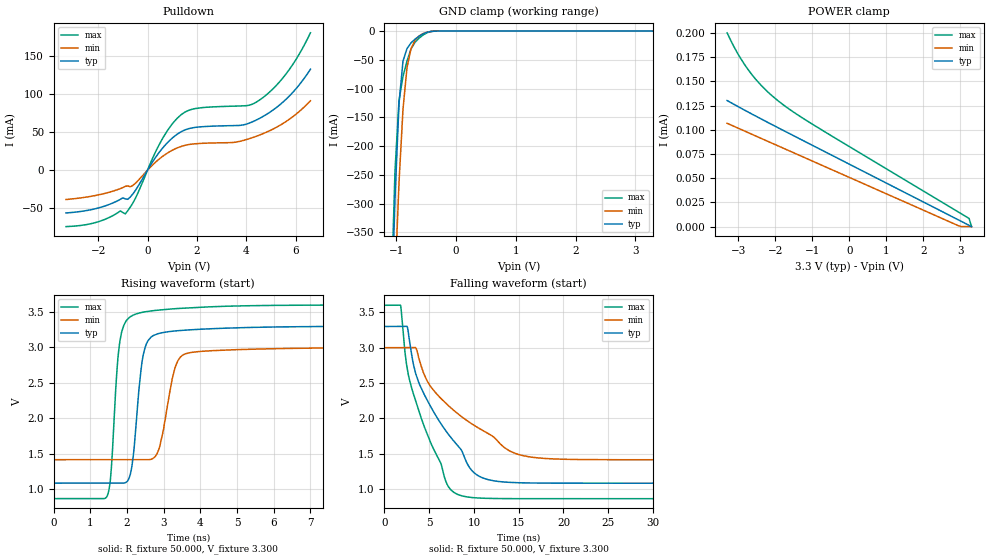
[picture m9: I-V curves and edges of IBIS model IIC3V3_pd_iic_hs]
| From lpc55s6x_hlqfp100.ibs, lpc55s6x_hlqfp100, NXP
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|   Model IIC3V3_pd_iic_hs
[Model] IIC3V3_pd_iic_hs
Model_type I/O_open_drain
Polarity   Non-Inverting
Enable   Active-Low
Vinl =  0.990V
Vinh =  2.310V
Vmeas =  1.650V
Cref =  0.0F
Rref =  100.000
Vref =  3.3V
C_comp   2.333pF   2.290pF   2.366pF
C_comp_pulldown   1.605pF   1.543pF   1.655pF
C_comp_power_clamp   0.444pF   0.380pF   0.497pF
[Model Spec]
Vinh   2.310V   2.100V   2.520V
Vinl   0.990V   0.900V   1.080V
Vmeas   1.650V   1.500V   1.800V
Vref   3.3V   3.0V   3.6V
Cref   0.0F   0.0F   0.0F
Rref   100.000   100.000   100.000
[Temperature Range]   25.000   0.125k   -40.000
[Voltage Range]   3.300V   3.000V   3.600V
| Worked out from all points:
|   slope of the pulldown table from 0 to 0.495 V, typ, clamps not added: 20.4 ohm
|   GND clamp passes 1 mA (typ) near -0.43 V on its own axis
|   rising waveform, R_fixture 50.000, V_fixture 3.300: 20-80 % time 247ps typ, 345ps min, 208ps max; typ from 1.08 V to 3.3 V
|   falling waveform, R_fixture 50.000, V_fixture 3.300: 20-80 % time 5.59ns typ, 7.99ns min, 3.92ns max; typ from 3.3 V to 1.08 V
[Pulldown]
|Voltage   I(typ)   I(min)   I(max)
-3.3V     -56mA      -38.4mA    -73.87mA
-2.1V     -50.37mA   -33.07mA   -68.52mA
-1.1V     -38.15mA   -24.11mA   -53.37mA
-900mV    -37.61mA   -21.16mA   -57.18mA
-500mV    -26.92mA   -17.4mA    -37.43mA
500mV     24.51mA    15.34mA    35.14mA
1.2V      47.07mA    29.16mA    67.89mA
1.9V      55.94mA    34.55mA    80.54mA
3.8V      58.93mA    38.34mA    84.23mA
4.5V      67.27mA    45.57mA    91.11mA
5.6V      92.6mA     63.56mA    125.7mA
6.6V      132.3mA    90.95mA    180mA
[GND_clamp]
|Voltage   I(typ)   I(min)   I(max)
-3.3V     -10.05A    -9.18A     -11.33A
-1.089V   -516.5mA   -633.7mA   -475mA
-1.022V   -291.9mA   -436.3mA   -243.2mA
-955mV    -126mA     -264mA     -120.7mA
-888mV    -52.17mA   -135.6mA   -79.12mA
-821mV    -30.44mA   -63.69mA   -52.12mA
-754mV    -20.67mA   -30.69mA   -31.05mA
-687mV    -14.19mA   -15.97mA   -19.65mA
-553mV    -5.021mA   -4.512mA   -7.044mA
-419mV    -659.6uA   -714.3uA   -896.4uA
-285mV    -20.38uA   -37.42uA   -22.84uA
3.3V      0A         0A         0A
[POWER_clamp]
|Voltage   I(typ)   I(min)   I(max)
-3.3V     130.3uA    106.8uA    200.3uA
-3.132V   126.7uA    103.9uA    187.1uA
-2.998V   123.9uA    101.7uA    177.8uA
-2.73V    118.4uA    97.1uA     162.1uA
-2.529V   114.3uA    93.69uA    152.3uA
-2.328V   110.2uA    90.28uA    143.9uA
-1.926V   102.2uA    83.47uA    130.1uA
-1.524V   94.32uA    76.66uA    118.8uA
-921mV    82.52uA    66.44uA    104uA
2.965V    6.549uA    592.5nA    14.59uA
3.233V    1.309uA    0A         8.433uA
3.3V      0A         0A         0A
[Ramp]
| variable   typ   min   max
dV/dt_r   1.327/0.248n   0.949/0.343n   1.638/0.209n
dV/dt_f   1.327/5.591n   0.949/7.984n   1.638/3.914n
R_load = 50.000
[Rising Waveform]
R_fixture= 50.000
V_fixture= 3.300
V_fixture_min= 3.000
V_fixture_max= 3.600
|time   V(typ)   V(min)   V(max)
0s        1.085V     1.415V     866.6mV
1.46ns    1.085V     1.415V     907.4mV
1.57ns    1.085V     1.415V     1.291V
1.78ns    1.085V     1.415V     2.996V
2.03ns    1.128V     1.415V     3.405V
2.58ns    3.098V     1.414V     3.506V
2.88ns    3.195V     1.58V      3.524V
3.45ns    3.236V     2.857V     3.548V
5.05ns    3.274V     2.967V     3.582V
250ns     3.297V     2.997V     3.596V
[Falling Waveform]
R_fixture= 50.000
V_fixture= 3.300
V_fixture_min= 3.000
V_fixture_max= 3.600
|time   V(typ)   V(min)   V(max)
0s        3.297V     2.997V     3.596V
1.8ns     3.297V     2.997V     3.597V
2.54ns    3.295V     2.997V     2.708V
2.88ns    3.036V     2.997V     2.504V
4.03ns    2.447V     2.772V     2.036V
7.01ns    1.799V     2.196V     1.068V
10.01ns   1.233V     1.902V     880.4mV
14.77ns   1.093V     1.499V     867.2mV
20.36ns   1.085V     1.422V     866.7mV
250ns     1.085V     1.415V     866.6mV
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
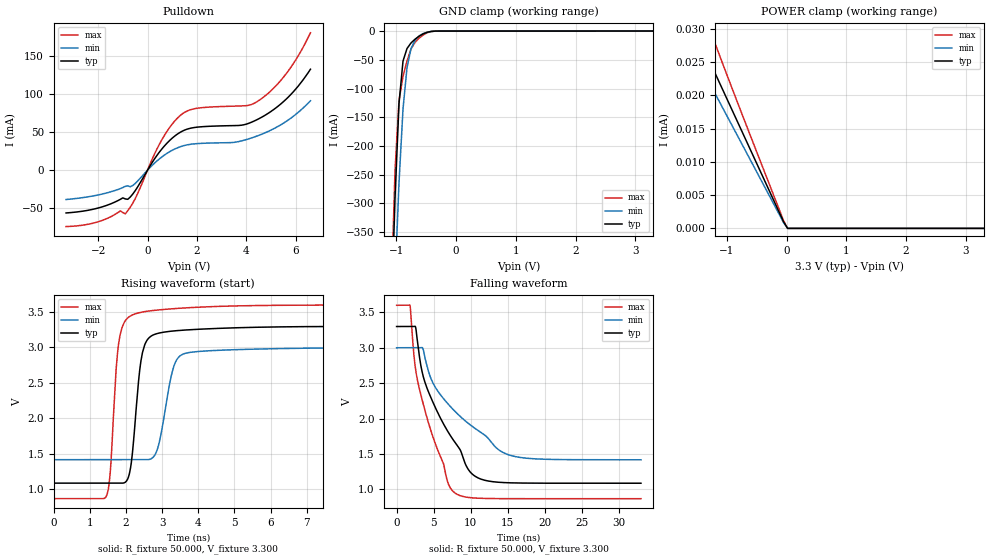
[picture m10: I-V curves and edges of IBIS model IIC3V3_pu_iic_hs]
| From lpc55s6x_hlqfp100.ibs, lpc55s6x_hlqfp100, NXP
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|   Model IIC3V3_pu_iic_hs
[Model] IIC3V3_pu_iic_hs
Model_type I/O_open_drain
Polarity   Non-Inverting
Enable   Active-Low
Vinl =  0.990V
Vinh =  2.310V
Vmeas =  1.650V
Cref =  0.0F
Rref =  100.000
Vref =  3.3V
C_comp   2.334pF   2.290pF   2.366pF
C_comp_pulldown   1.603pF   1.543pF   1.653pF
C_comp_power_clamp   0.446pF   0.383pF   0.498pF
[Model Spec]
Vinh   2.310V   2.100V   2.520V
Vinl   0.990V   0.900V   1.080V
Vmeas   1.650V   1.500V   1.800V
Vref   3.3V   3.0V   3.6V
Cref   0.0F   0.0F   0.0F
Rref   100.000   100.000   100.000
[Temperature Range]   25.000   0.125k   -40.000
[Voltage Range]   3.300V   3.000V   3.600V
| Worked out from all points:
|   slope of the pulldown table from 0 to 0.495 V, typ, clamps not added: 20.4 ohm
|   GND clamp passes 1 mA (typ) near -0.43 V on its own axis
|   rising waveform, R_fixture 50.000, V_fixture 3.300: 20-80 % time 249ps typ, 343ps min, 208ps max; typ from 1.09 V to 3.3 V
|   falling waveform, R_fixture 50.000, V_fixture 3.300: 20-80 % time 5.6ns typ, 7.99ns min, 3.92ns max; typ from 3.3 V to 1.09 V
[Pulldown]
|Voltage   I(typ)   I(min)   I(max)
-3.3V     -56mA      -38.4mA    -73.87mA
-2.1V     -50.37mA   -33.07mA   -68.52mA
-1.1V     -38.15mA   -24.11mA   -53.37mA
-900mV    -37.61mA   -21.16mA   -57.18mA
-500mV    -26.92mA   -17.4mA    -37.43mA
500mV     24.51mA    15.34mA    35.14mA
1.2V      47.07mA    29.16mA    67.89mA
1.9V      55.94mA    34.55mA    80.54mA
3.8V      58.93mA    38.34mA    84.23mA
4.5V      67.27mA    45.57mA    91.11mA
5.6V      92.6mA     63.56mA    125.7mA
6.6V      132.3mA    90.95mA    180mA
[GND_clamp]
|Voltage   I(typ)   I(min)   I(max)
-3.3V     -10.05A    -9.18A     -11.33A
-1.089V   -516.6mA   -633.8mA   -475.1mA
-1.022V   -291.9mA   -436.4mA   -243.3mA
-955mV    -126.1mA   -264.1mA   -120.8mA
-888mV    -52.24mA   -135.7mA   -79.2mA
-821mV    -30.5mA    -63.74mA   -52.2mA
-754mV    -20.73mA   -30.74mA   -31.13mA
-687mV    -14.25mA   -16.02mA   -19.73mA
-553mV    -5.085mA   -4.563mA   -7.127mA
-419mV    -724uA     -765.2uA   -978.9uA
-285mV    -84.74uA   -88.26uA   -105.4uA
3.3V      0A         0A         0A
[POWER_clamp]
|Voltage   I(typ)   I(min)   I(max)
-3.3V     65.36uA    55.62uA    117.1uA
-1.792V   34.89uA    30.26uA    43.22uA
-1.725V   33.58uA    29.13uA    41.33uA
-1.524V   29.67uA    25.75uA    35.94uA
-1.323V   25.75uA    22.36uA    30.85uA
-1.256V   24.45uA    21.23uA    29.21uA
-921mV    17.94uA    15.59uA    21.23uA
-318mV    6.202uA    5.398uA    7.298uA
-50mV     976.9nA    858.9nA    1.15uA
17mV      0A         0A         0A
3.3V      0A         0A         0A
[Ramp]
| variable   typ   min   max
dV/dt_r   1.328/0.248n   0.950/0.343n   1.639/0.209n
dV/dt_f   1.328/5.600n   0.950/7.993n   1.639/3.922n
R_load = 50.000
[Rising Waveform]
R_fixture= 50.000
V_fixture= 3.300
V_fixture_min= 3.000
V_fixture_max= 3.600
|time   V(typ)   V(min)   V(max)
0s        1.086V     1.417V     867.9mV
1.471ns   1.086V     1.417V     922.7mV
1.566ns   1.086V     1.417V     1.262V
1.769ns   1.086V     1.417V     2.949V
2.016ns   1.118V     1.417V     3.401V
2.514ns   3.033V     1.416V     3.505V
2.873ns   3.198V     1.574V     3.528V
3.364ns   3.235V     2.789V     3.549V
3.895ns   3.254V     2.938V     3.565V
33ns      3.3V       3V         3.6V
[Falling Waveform]
R_fixture= 50.000
V_fixture= 3.300
V_fixture_min= 3.000
V_fixture_max= 3.600
|time   V(typ)   V(min)   V(max)
0s        3.3V       3V         3.6V
1.807ns   3.3V       3V         3.599V
2.556ns   3.294V     3V         2.702V
3.031ns   2.916V     3V         2.441V
4.289ns   2.382V     2.674V     1.944V
7.782ns   1.679V     2.112V     956.5mV
9.912ns   1.248V     1.913V     882.8mV
12.01ns   1.125V     1.757V     871.2mV
16.64ns   1.089V     1.451V     868.1mV
33ns      1.086V     1.417V     867.9mV
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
